VERSION 5.7 ;
  NOWIREEXTENSIONATPIN ON ;
  DIVIDERCHAR "/" ;
  BUSBITCHARS "[]" ;
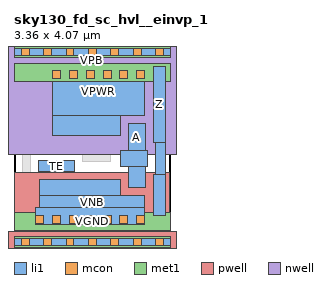
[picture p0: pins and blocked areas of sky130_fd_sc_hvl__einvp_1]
MACRO sky130_fd_sc_hvl__einvp_1
  CLASS BLOCK ;
  FOREIGN sky130_fd_sc_hvl__einvp_1 ;
  ORIGIN 0.000 0.000 ;
  SIZE 3.360 BY 4.070 ;
  PIN A
    ANTENNAGATEAREA 1.125000 ;
    PORT
      LAYER li1 ;
        RECT 2.445 1.955 2.810 2.540 ;
        RECT 2.275 1.625 2.865 1.955 ;
        RECT 2.445 1.160 2.810 1.625 ;
    END
  END A
  PIN TE
    ANTENNAGATEAREA 0.960000 ;
    PORT
      LAYER li1 ;
        RECT 0.515 1.505 1.305 1.750 ;
    END
  END TE
  PIN VGND
    USE GROUND ;
    PORT
      LAYER li1 ;
        RECT 0.550 0.990 2.275 1.335 ;
        RECT 0.550 0.735 2.800 0.990 ;
        RECT 0.470 0.365 2.800 0.735 ;
      LAYER mcon ;
        RECT 0.470 0.395 0.640 0.565 ;
        RECT 0.830 0.395 1.000 0.565 ;
        RECT 1.190 0.395 1.360 0.565 ;
        RECT 1.550 0.395 1.720 0.565 ;
        RECT 1.910 0.395 2.080 0.565 ;
        RECT 2.270 0.395 2.440 0.565 ;
        RECT 2.630 0.395 2.800 0.565 ;
      LAYER met1 ;
        RECT 0.000 0.255 3.360 0.625 ;
    END
  END VGND
  PIN VNB
    ANTENNADIFFAREA 0.571200 ;
    PORT
      LAYER pwell ;
        RECT 0.020 0.215 3.340 1.495 ;
        RECT -0.130 -0.215 3.490 0.215 ;
      LAYER li1 ;
        RECT 0.000 -0.085 3.360 0.085 ;
      LAYER mcon ;
        RECT 0.155 -0.085 0.325 0.085 ;
        RECT 0.635 -0.085 0.805 0.085 ;
        RECT 1.115 -0.085 1.285 0.085 ;
        RECT 1.595 -0.085 1.765 0.085 ;
        RECT 2.075 -0.085 2.245 0.085 ;
        RECT 2.555 -0.085 2.725 0.085 ;
        RECT 3.035 -0.085 3.205 0.085 ;
      LAYER met1 ;
        RECT 0.000 -0.115 3.360 0.115 ;
    END
  END VNB
  PIN VPB
    ANTENNADIFFAREA 0.571200 ;
    PORT
      LAYER nwell ;
        RECT -0.330 1.885 3.690 4.485 ;
      LAYER li1 ;
        RECT 0.000 3.985 3.360 4.155 ;
      LAYER mcon ;
        RECT 0.155 3.985 0.325 4.155 ;
        RECT 0.635 3.985 0.805 4.155 ;
        RECT 1.115 3.985 1.285 4.155 ;
        RECT 1.595 3.985 1.765 4.155 ;
        RECT 2.075 3.985 2.245 4.155 ;
        RECT 2.555 3.985 2.725 4.155 ;
        RECT 3.035 3.985 3.205 4.155 ;
      LAYER met1 ;
        RECT 0.000 3.955 3.360 4.185 ;
    END
  END VPB
  PIN VPWR
    USE POWER ;
    PORT
      LAYER li1 ;
        RECT 0.830 2.710 2.800 3.755 ;
        RECT 0.830 2.280 2.275 2.710 ;
      LAYER mcon ;
        RECT 0.830 3.505 1.000 3.675 ;
        RECT 1.190 3.505 1.360 3.675 ;
        RECT 1.550 3.505 1.720 3.675 ;
        RECT 1.910 3.505 2.080 3.675 ;
        RECT 2.270 3.505 2.440 3.675 ;
        RECT 2.630 3.505 2.800 3.675 ;
      LAYER met1 ;
        RECT 0.000 3.445 3.360 3.815 ;
    END
  END VPWR
  PIN Z
    ANTENNADIFFAREA 0.641250 ;
    PORT
      LAYER li1 ;
        RECT 2.980 2.125 3.235 3.755 ;
        RECT 3.035 1.455 3.235 2.125 ;
        RECT 2.980 0.575 3.235 1.455 ;
    END
  END Z
  OBS
      LAYER li1 ;
        RECT 0.175 2.100 0.650 3.005 ;
        RECT 0.175 1.930 2.065 2.100 ;
        RECT 0.175 1.335 0.345 1.930 ;
        RECT 1.475 1.725 2.065 1.930 ;
        RECT 0.175 0.905 0.380 1.335 ;
  END
END sky130_fd_sc_hvl__einvp_1
END LIBRARY

